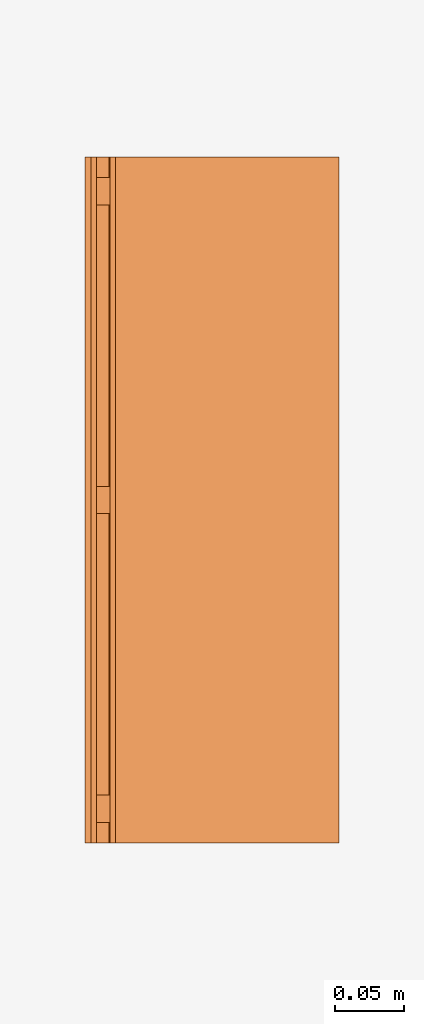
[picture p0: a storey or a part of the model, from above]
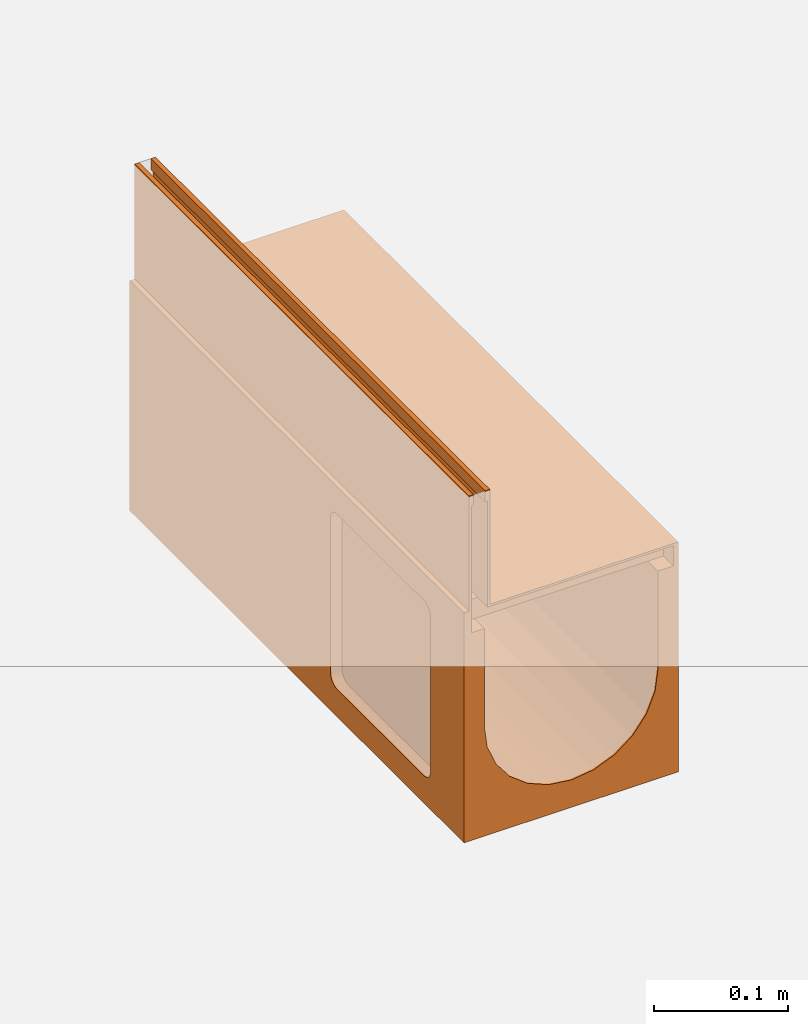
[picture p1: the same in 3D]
Properties of the parts of a building model (IFC2X3)

# File
Description: ViewDefinition [CoordinationView]
File name: 24153 - No 0.1J Constant Depth Channel - 500mm LG - Invert Depth 185mm.ifc
Time: 2013-10-30T13:30:15
Written by: Autodesk Revit 2013
Made in: 20120221_2030(x64)

# IfcProject, Project Number
LongName: Project Name; Phase: Project Status

# IfcSite, Default
RefLatitude: 42, 21, 30, 344238; RefLongitude: -71, -3, -35, -194702; RefElevation: 0 mm

# IfcBuilding
Pset_BuildingCommon - NumberOfStoreys: 1
Other - Project Number: Project Number; Project Name: Project Name; Project Status: Project Status; Project Issue Date: Issue Date; Client Name: Owner; Project Address: ## Street City, State Zip

# IfcBuildingStorey, Level 1
LongName: Level 1; Elevation: 0 mm
Constraints - Elevation Base: 0; Elevation: 0 mm
Graphics - Symbol: M_Level Head - Circle: M_Level Head - Circle; Symbol at End 1 Default: no; Symbol at End 2 Default: yes; Line Pattern: Center; Line Weight: 1; Color: 0
Identity Data - Name: Level 1; Structural: no; Building Story: yes
Dimensions - Computation Height: 0 mm

# IfcBuildingElementProxy: 24153 - No 0.1J Constant Depth Channel - 500mm LG - Invert Depth 185mm, Civil-Drainage-Channel-ACO-MultiDrain-M150DS-Brickslot-Channel-System:24153 - No 0.1J Constant Depth Channel - 500mm LG - Invert Depth 185mm:24153 - No 0.1J Constant Depth Channel - 500mm LG - Invert Depth 185mm:196059
In: Level 1
Material: Stainless Steel (F), Vienite® Synthetic Resin Concrete
Phasing - Phase Created: New Construction
Dimensions - Brickslot Access Unit Void Bottom Depth: 5895 mm; Volume: 6289628 mm3; Brickslot Access Unit Void Depth: 6000 mm; Brickslot Grating Void Depth: 0 mm; EndCap Position: 500 mm; Length: 1000 mm; Brickslot Void Length: -500 mm; FloorCut_Length: -500 mm; Custom_Void_Length: 0 mm; FloorCut_Width: 185 mm; InvDepth: 110 mm; FloorCut_HorPosition: 92.5 mm; Floor cut gap depth for access unit: 105 mm; Depth: 210 mm; Floor Cut Gap: 105 mm; FloorCut_Depth: 210 mm; GratingLength: 0 mm; Length Drain: -500 mm; EndCap_Height: -210 mm
Constraints - Level: Level: Level 1; Moves With Nearby Elements: no
Construction - 23159_Universal Endcap (Female End): no; 23186_Load Class C250 & D400_Brickslot Grating_Stainless Steel_500mm Long: yes; 23159_Universal Endcap (Male End): no; 23185_Load Class C250 & D400_Brickslot Grating_Stainless Steel_1000mm Long: no; 24187_Load Class C250 & D400_Brickslot_Access Unit_Stainless Steel_500mm Long: no; 24157_Shallow Depth Channel with seal: no; Constant Depth Channel_1000: no; 24158_Sump Unit: no; 24156_Shallow Depth Channel: no; Constant Depth Channel_500: yes
Pset_BuildingElementProxyCommon - Reference: 24153 - No 0.1J Constant Depth Channel - 500mm LG - Invert Depth 185mm
Identity Data - Price: POA - contact ACO; Cost: 0; Assembly Code: D2040; Manufacturer: ACO Technologies plc - ACO Water Management Division; Watermarked With: BIM Manager Premium Suite; Type Comments: ACO MultiDrain M150DS 0.1J Constant Depth Channel 500mm Long; Product Code: 24153; Model: ACO MultiDrain MDS Brickslot - M150DS; Watermark 2: This file is water marked and users are prohibited to reproduce, adapt, distribute this information; OmniClass Title: Rainwater Removal; Model Description: Channel drainage system; Fax: +44 (0)1462 815895; Maintenance guidelines: http://www.aco.co.uk/download.php?id=173; e-mail Technical: technical@aco.co.uk; URL: www.aco.co.uk; Watermarked By: www.aco.co.uk; OmniClass Number: 23.70.50.24; Assembly Description: Rain Water Drainage; Product brochure: http://www.aco.co.uk/download.php?id=173; Watermark 1: This file is the property of ACO Technologies PLC; Address: ACO Business Park, Hitchin Road, Shefford, Bedfordshire, United Kingdom SG17 5TE; e-mail Sales: customersupport@aco.co.uk; Product Page URL: http://www.aco.co.uk/product_detail.php?id=58; Installation guidelines: http://www.aco.co.uk/download.php?id=173; Telephone: +44 (0)1462 816666
Data - Product Weight: 12.7Kg; Pre-formed Outlet Ø: N/A; Channel C.S.A: 0.020m²; Product Standard: BS EN 1433:2002, CE marked; Hydraulic Performance: http://www.aco.co.uk/download.php?id=173; Concrete Surround Volume - Load Class B 125 - C 250 - Concrete Pavement: 0.14m³/m; Concrete Surround Volume - Load Class D 400 - Concrete Pavement: 0.21m³/m; ACO Hydraulic Design Software: http://www.acodesign.co.uk; Product Dimensions: 500mm x 185mm x 210mm (LxWxH); Installation - Concrete Grade: Refer to brochure; Concrete Surround Volume - Load Class A 15 - Concrete Pavement: 0.09m³/m; Load Class: A 15 - D 400; Invert Depth: 185mm
Materials and Finishes - Channel Material: Vienite® Synthetic Resin Concrete; Edge Rail Material: Stainless Steel Grade 304; Channel Colour: Brown; Edge Rail Colour: Self
Model Properties - End Cap Product code 23219: No. 306 Universal End Cap - 185mm wide x 310mm long - Spigot Ø110mm x 50mm long - Silver - Co-Polymer Polypropylene - 0.3kg; Brickslot Access Unit Product code 23187: Load Class C250/D400 - Brickslot Access Unit Stainless Steel - 500mm long x 105mm high - 10mm Slot - Intake area 10000mm²/m - 6.4kg; Brickslot Grating Product code 23185: N/A; Brickslot Grating Product code 23186: Load Class C250/D400 -Brickslot Stainless Steel - 500mm long x 105mm high - 10mm Slot - Intake area 10000mm²/m - 3.8kg
General - SerialNumber: 0; TagNumber: 0
Green Building Properties - Edge Rail Recyclable: Fully recyclable; Channel Recycled Material Content: 20% minimum; Edge Rail Recycled Material Content: Between 40% - 90%; Channel Recyclable: Fully recyclable
Other - CreatedBy: www.aco.co.uk; Revision: 1

# IfcOpeningElement: Recess (2)
In: Level 1
Phasing - Phase Created: New Construction
Dimensions - Perimeter: 20000 mm; Volume: 9979630000 mm3; Area: 25000000 mm2; Thickness: 400 mm
Structural - Structural: no; Enable Analytical Model: no
Constraints - Related to Mass: no; Room Bounding: yes; Height Offset From Level: 0 mm; Level: Level: Level 1
Construction - Function: 0; Default Thickness: 400 mm
Analytical Properties - Thermal Resistance (R): 0.477897; Heat Transfer Coefficient (U): 2.0925; Thermal mass: 543920; Absorptance: 0.1; Roughness: 1
Graphics - Coarse Scale Fill Color: 0
Materials and Finishes - Structural Material: Earth

# IfcSlab: Floor:Generic Floor - 400mm, Floor:Generic Floor - 400mm:193825
In: Level 1
PredefinedType: FLOOR; Material: Earth 400 mm
Phasing - Phase Created: New Construction
Dimensions - Perimeter: 20000 mm; Volume: 9979630000 mm3; Area: 25000000 mm2; Thickness: 400 mm
Structural - Structural: no; Enable Analytical Model: no
Constraints - Related to Mass: no; Room Bounding: yes; Height Offset From Level: 0 mm; Level: Level: Level 1
Pset_SlabCommon - Reference: Generic Floor - 400mm; IsExternal: no; LoadBearing: yes
Construction - Function: 0; Default Thickness: 400 mm
Analytical Properties - Thermal Resistance (R): 0.477897; Heat Transfer Coefficient (U): 2.0925; Thermal mass: 543920; Absorptance: 0.1; Roughness: 1
Graphics - Coarse Scale Fill Color: 0
Materials and Finishes - Structural Material: Earth
